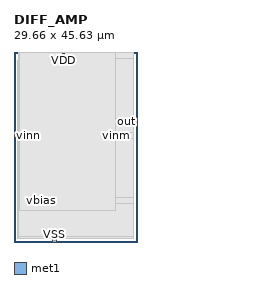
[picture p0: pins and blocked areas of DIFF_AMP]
MACRO DIFF_AMP
  CLASS BLOCK ;
  FOREIGN DIFF_AMP ;
  ORIGIN -11.950 15.550 ;
  SIZE 29.660 BY 45.630 ;
  PIN VDD
    ANTENNADIFFAREA 35.963600 ;
    PORT
      LAYER met1 ;
        RECT 23.540 28.780 24.090 29.780 ;
    END
  END VDD
  PIN vinm
    ANTENNAGATEAREA 20.000000 ;
    PORT
      LAYER met1 ;
        RECT 35.960 9.470 36.960 10.470 ;
    END
  END vinm
  PIN vinn
    ANTENNAGATEAREA 20.000000 ;
    PORT
      LAYER met1 ;
        RECT 11.950 9.585 12.950 10.585 ;
    END
  END vinn
  PIN vbias
    ANTENNAGATEAREA 8.000000 ;
    PORT
      LAYER met1 ;
        RECT 18.110 -6.050 19.110 -5.050 ;
    END
  END vbias
  PIN VSS
    ANTENNADIFFAREA 16.973999 ;
    PORT
      LAYER met1 ;
        RECT 21.180 -15.550 22.180 -14.550 ;
    END
  END VSS
  PIN out
    ANTENNADIFFAREA 23.199999 ;
    PORT
      LAYER met1 ;
        RECT 40.610 12.890 41.610 13.890 ;
    END
  END out
  OBS
      LAYER nwell ;
        RECT 12.680 -14.370 36.320 26.640 ;
      LAYER li1 ;
        RECT 12.860 -14.690 36.140 28.040 ;
      LAYER met1 ;
        RECT 12.950 28.500 23.260 30.030 ;
        RECT 24.370 28.500 40.610 30.030 ;
        RECT 12.950 14.170 40.610 28.500 ;
        RECT 12.950 12.610 40.330 14.170 ;
        RECT 12.950 10.865 40.610 12.610 ;
        RECT 13.230 10.750 40.610 10.865 ;
        RECT 13.230 9.305 35.680 10.750 ;
        RECT 12.950 9.190 35.680 9.305 ;
        RECT 37.240 9.190 40.610 10.750 ;
        RECT 12.950 -4.770 40.610 9.190 ;
        RECT 12.950 -6.330 17.830 -4.770 ;
        RECT 19.390 -6.330 40.610 -4.770 ;
        RECT 12.950 -14.270 40.610 -6.330 ;
        RECT 12.950 -14.720 20.900 -14.270 ;
        RECT 22.460 -14.720 40.610 -14.270 ;
      LAYER met2 ;
        RECT 13.270 -7.940 36.310 30.080 ;
  END
END DIFF_AMP
END LIBRARY

